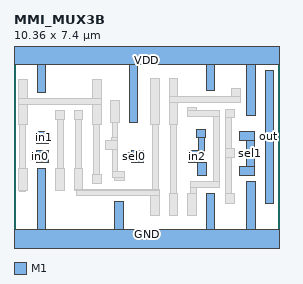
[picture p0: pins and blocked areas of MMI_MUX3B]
MACRO MMI_MUX3B
	CLASS CORE ;
	FOREIGN MMI_MUX3B 0 0 ;
	SIZE 10.36 BY 7.4 ;
	SYMMETRY X Y ;
	SITE CORE1 ;
	PIN out
		DIRECTION output ;
		USE SIGNAL ;
		PORT
			LAYER M1 ;
			RECT 9.78 1.51 10.12 6.67 ;
		END
		AntennaDiffArea 1.3248 ;
	END out
	PIN in1
		DIRECTION input ;
		USE SIGNAL ;
		PORT
			LAYER M1 ;
			RECT 0.885 4.24 1.335 4.295 ;
			LAYER M1 ;
			RECT 0.885 3.9 1.435 4.24 ;
			LAYER M1 ;
			RECT 0.885 3.845 1.335 3.9 ;
		END
		AntennaGateArea 0.4968 ;
	END in1
	PIN sel0
		DIRECTION input ;
		USE SIGNAL ;
		PORT
			LAYER M1 ;
			RECT 4.585 3.5 5.035 3.555 ;
			LAYER M1 ;
			RECT 4.29 3.16 5.035 3.5 ;
			LAYER M1 ;
			RECT 4.585 3.105 5.035 3.16 ;
		END
		AntennaGateArea 0.7452 ;
	END sel0
	PIN GND
		DIRECTION inout ;
		USE GROUND ;
		PORT
			LAYER M1 ;
			RECT 0.9 0.5 1.24 2.865 ;
			LAYER M1 ;
			RECT 3.93 0.5 4.27 1.565 ;
			LAYER M1 ;
			RECT 7.485 0.5 7.825 1.88 ;
			LAYER M1 ;
			RECT 9.06 0.5 9.4 2.35 ;
			LAYER M1 ;
			RECT 0 -0.5 10.36 0.5 ;
		END
	END GND
	PIN in2
		DIRECTION input ;
		USE SIGNAL ;
		PORT
			LAYER M1 ;
			RECT 7.125 4.055 7.465 4.395 ;
			LAYER M1 ;
			RECT 7.195 3.55 7.425 4.055 ;
			LAYER M1 ;
			RECT 6.805 3.1 7.425 3.55 ;
			LAYER M1 ;
			RECT 7.165 2.575 7.505 3.1 ;
		END
		AntennaGateArea 0.4968 ;
	END in2
	PIN sel1
		DIRECTION input ;
		USE SIGNAL ;
		PORT
			LAYER M1 ;
			RECT 8.79 3.96 9.36 4.3 ;
			LAYER M1 ;
			RECT 9.055 2.925 9.36 3.96 ;
			LAYER M1 ;
			RECT 8.79 2.585 9.36 2.925 ;
		END
		AntennaGateArea 0.7452 ;
	END sel1
	PIN VDD
		DIRECTION inout ;
		USE POWER ;
		PORT
			LAYER M1 ;
			RECT 0 6.9 10.36 7.9 ;
			LAYER M1 ;
			RECT 0.9 5.81 1.24 6.9 ;
			LAYER M1 ;
			RECT 4.48 4.67 4.82 6.9 ;
			LAYER M1 ;
			RECT 7.485 5.91 7.825 6.9 ;
			LAYER M1 ;
			RECT 9.06 4.91 9.4 6.9 ;
		END
	END VDD
	PIN in0
		DIRECTION input ;
		USE SIGNAL ;
		PORT
			LAYER M1 ;
			RECT 0.885 3.5 1.335 3.555 ;
			LAYER M1 ;
			RECT 0.66 3.16 1.335 3.5 ;
			LAYER M1 ;
			RECT 0.885 3.105 1.335 3.16 ;
		END
		AntennaGateArea 0.4968 ;
	END in0
	OBS
		LAYER M1 ;
		RECT 0.18 5.58 0.52 6.345 ;
		LAYER M1 ;
		RECT 3.06 5.58 3.4 6.345 ;
		LAYER M1 ;
		RECT 0.18 5.35 3.4 5.58 ;
		LAYER M1 ;
		RECT 0.18 4.585 0.52 5.35 ;
		LAYER M1 ;
		RECT 1.62 4.78 1.96 5.12 ;
		LAYER M1 ;
		RECT 2.34 4.78 2.68 5.12 ;
		LAYER M1 ;
		RECT 0.2 2.865 0.43 4.585 ;
		LAYER M1 ;
		RECT 1.7 2.865 1.93 4.78 ;
		LAYER M1 ;
		RECT 2.4 2.865 2.63 4.78 ;
		LAYER M1 ;
		RECT 3.06 4.585 3.4 5.35 ;
		LAYER M1 ;
		RECT 3.76 4.67 4.1 5.51 ;
		LAYER M1 ;
		RECT 0.18 2.025 0.52 2.865 ;
		LAYER M1 ;
		RECT 0.2 1.985 0.43 2.025 ;
		LAYER M1 ;
		RECT 1.62 2.025 1.96 2.865 ;
		LAYER M1 ;
		RECT 2.34 2.035 2.68 2.865 ;
		LAYER M1 ;
		RECT 3.095 2.62 3.325 4.585 ;
		LAYER M1 ;
		RECT 3.82 4.075 4.05 4.67 ;
		LAYER M1 ;
		RECT 5.325 4.595 5.665 6.355 ;
		LAYER M1 ;
		RECT 6.045 5.68 6.385 6.355 ;
		LAYER M1 ;
		RECT 8.49 5.68 8.83 5.97 ;
		LAYER M1 ;
		RECT 6.045 5.45 8.83 5.68 ;
		LAYER M1 ;
		RECT 6.045 4.595 6.385 5.45 ;
		LAYER M1 ;
		RECT 6.765 5.11 7.105 5.22 ;
		LAYER M1 ;
		RECT 6.765 4.88 8.015 5.11 ;
		LAYER M1 ;
		RECT 3.81 3.935 4.05 4.075 ;
		LAYER M1 ;
		RECT 3.56 3.595 4.05 3.935 ;
		LAYER M1 ;
		RECT 3.82 2.735 4.05 3.595 ;
		LAYER M1 ;
		RECT 3.06 2.28 3.4 2.62 ;
		LAYER M1 ;
		RECT 3.82 2.495 4.285 2.735 ;
		LAYER M1 ;
		RECT 3.905 2.395 4.285 2.495 ;
		LAYER M1 ;
		RECT 5.385 2.035 5.615 4.595 ;
		LAYER M1 ;
		RECT 2.34 2.025 5.665 2.035 ;
		LAYER M1 ;
		RECT 1.7 1.995 1.93 2.025 ;
		LAYER M1 ;
		RECT 2.45 1.805 5.665 2.025 ;
		LAYER M1 ;
		RECT 6.1 1.88 6.33 4.595 ;
		LAYER M1 ;
		RECT 7.785 2.345 8.015 4.88 ;
		LAYER M1 ;
		RECT 6.875 2.115 8.015 2.345 ;
		LAYER M1 ;
		RECT 8.245 4.84 8.585 5.18 ;
		LAYER M1 ;
		RECT 8.245 3.625 8.475 4.84 ;
		LAYER M1 ;
		RECT 8.245 3.285 8.605 3.625 ;
		LAYER M1 ;
		RECT 6.875 1.88 7.105 2.115 ;
		LAYER M1 ;
		RECT 8.245 1.88 8.475 3.285 ;
		LAYER M1 ;
		RECT 5.325 1.04 5.665 1.805 ;
		LAYER M1 ;
		RECT 6.045 1.04 6.385 1.88 ;
		LAYER M1 ;
		RECT 6.765 1.04 7.105 1.88 ;
		LAYER M1 ;
		RECT 8.245 1.5 8.585 1.88 ;
	END
END MMI_MUX3B
